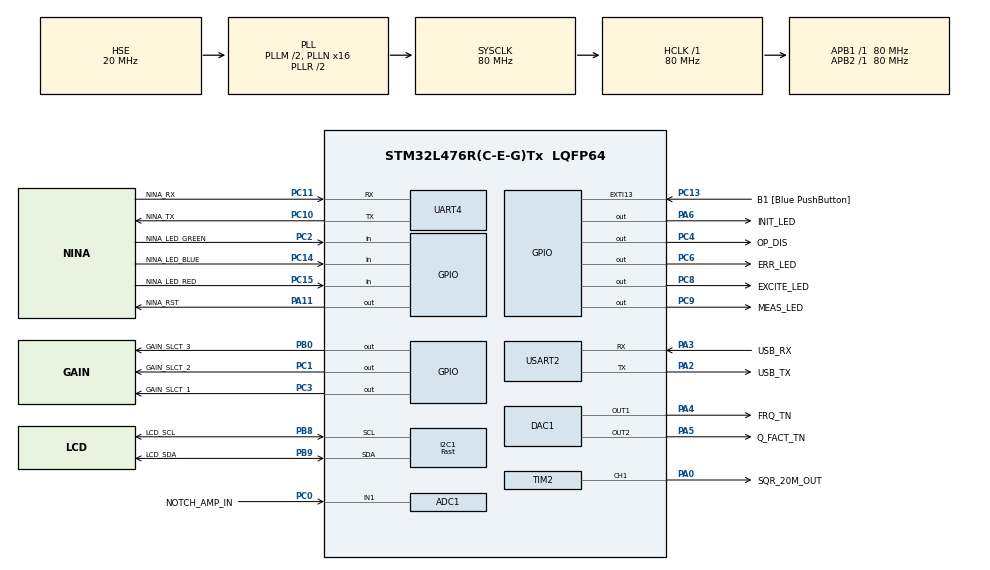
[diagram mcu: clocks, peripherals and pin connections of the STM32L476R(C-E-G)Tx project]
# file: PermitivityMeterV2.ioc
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ADC1.Channel-0\#ChannelRegularConversion=ADC_CHANNEL_1
ADC1.ContinuousConvMode=ENABLE
ADC1.DMAContinuousRequests=ENABLE
ADC1.NbrOfConversionFlag=1
ADC1.OffsetNumber-0\#ChannelRegularConversion=ADC_OFFSET_NONE
ADC1.OversamplingMode=DISABLE
ADC1.Rank-0\#ChannelRegularConversion=1
ADC1.SamplingTime-0\#ChannelRegularConversion=ADC_SAMPLETIME_47CYCLES_5
ADC1.master=1
DAC1.DAC_Channel-DAC_OUT2_ExtAndInt=DAC_CHANNEL_2
Dma.ADC1.0.Direction=DMA_PERIPH_TO_MEMORY
Dma.ADC1.0.Instance=DMA1_Channel1
Dma.ADC1.0.MemDataAlignment=DMA_MDATAALIGN_HALFWORD
Dma.ADC1.0.MemInc=DMA_MINC_ENABLE
Dma.ADC1.0.Mode=DMA_CIRCULAR
Dma.ADC1.0.PeriphDataAlignment=DMA_PDATAALIGN_HALFWORD
Dma.ADC1.0.PeriphInc=DMA_PINC_DISABLE
Dma.ADC1.0.Priority=DMA_PRIORITY_HIGH
Dma.DAC_CH1.2.Direction=DMA_MEMORY_TO_PERIPH
Dma.DAC_CH1.2.Instance=DMA1_Channel3
Dma.DAC_CH1.2.MemDataAlignment=DMA_MDATAALIGN_HALFWORD
Dma.DAC_CH1.2.MemInc=DMA_MINC_ENABLE
Dma.DAC_CH1.2.Mode=DMA_NORMAL
Dma.DAC_CH1.2.PeriphDataAlignment=DMA_PDATAALIGN_HALFWORD
Dma.DAC_CH1.2.PeriphInc=DMA_PINC_DISABLE
Dma.DAC_CH1.2.Priority=DMA_PRIORITY_LOW
Dma.DAC_CH2.1.Direction=DMA_MEMORY_TO_PERIPH
Dma.DAC_CH2.1.Instance=DMA1_Channel4
Dma.DAC_CH2.1.MemDataAlignment=DMA_MDATAALIGN_HALFWORD
Dma.DAC_CH2.1.MemInc=DMA_MINC_ENABLE
Dma.DAC_CH2.1.Mode=DMA_NORMAL
Dma.DAC_CH2.1.PeriphDataAlignment=DMA_PDATAALIGN_HALFWORD
Dma.DAC_CH2.1.PeriphInc=DMA_PINC_DISABLE
Dma.DAC_CH2.1.Priority=DMA_PRIORITY_LOW
Dma.Request0=ADC1
Dma.Request1=DAC_CH2
Dma.Request2=DAC_CH1
Dma.Request3=USART2_RX
Dma.Request4=USART2_TX
Dma.USART2_RX.3.Direction=DMA_PERIPH_TO_MEMORY
Dma.USART2_RX.3.Instance=DMA1_Channel6
Dma.USART2_RX.3.MemDataAlignment=DMA_MDATAALIGN_BYTE
Dma.USART2_RX.3.MemInc=DMA_MINC_ENABLE
Dma.USART2_RX.3.Mode=DMA_NORMAL
Dma.USART2_RX.3.PeriphDataAlignment=DMA_PDATAALIGN_BYTE
Dma.USART2_RX.3.PeriphInc=DMA_PINC_DISABLE
Dma.USART2_RX.3.Priority=DMA_PRIORITY_LOW
Dma.USART2_TX.4.Direction=DMA_MEMORY_TO_PERIPH
Dma.USART2_TX.4.Instance=DMA1_Channel7
Dma.USART2_TX.4.MemDataAlignment=DMA_MDATAALIGN_BYTE
Dma.USART2_TX.4.MemInc=DMA_MINC_ENABLE
Dma.USART2_TX.4.Mode=DMA_NORMAL
Dma.USART2_TX.4.PeriphDataAlignment=DMA_PDATAALIGN_BYTE
Dma.USART2_TX.4.PeriphInc=DMA_PINC_DISABLE
Dma.USART2_TX.4.Priority=DMA_PRIORITY_LOW
I2C1.I2C_Speed_Mode=I2C_Fast
I2C1.Timing=0x00F12981
IWDG.Prescaler=IWDG_PRESCALER_256
Mcu.Family=STM32L4
Mcu.Name=STM32L476R(C-E-G)Tx
Mcu.Package=LQFP64
NVIC.DMA1_Channel1_IRQn=true\:0\:0\:false\:false\:true\:false\:true\:true
NVIC.DMA1_Channel3_IRQn=true\:0\:0\:false\:false\:true\:false\:true\:true
NVIC.DMA1_Channel4_IRQn=true\:0\:0\:false\:false\:true\:false\:true\:true
NVIC.DMA1_Channel6_IRQn=true\:0\:0\:false\:false\:true\:false\:true\:true
NVIC.DMA1_Channel7_IRQn=true\:0\:0\:false\:false\:true\:false\:true\:true
NVIC.PriorityGroup=NVIC_PRIORITYGROUP_4
NVIC.USART2_IRQn=true\:0\:0\:false\:false\:true\:true\:true\:true
PA0.GPIO_Label=SQR_20M_OUT
PA0.GPIO_ModeDefaultPP=GPIO_MODE_AF_PP
PA0.GPIO_PuPd=GPIO_NOPULL
PA0.GPIO_Speed=GPIO_SPEED_FREQ_VERY_HIGH
PA0.Signal=S_TIM2_CH1
PA11.GPIO_Label=NINA_RST 
PA11.Signal=GPIO_Output
PA13\ (JTMS-SWDIO).GPIO_Label=TMS
PA13\ (JTMS-SWDIO).Mode=Trace_Asynchronous_SW
PA13\ (JTMS-SWDIO).Signal=SYS_JTMS-SWDIO
PA14\ (JTCK-SWCLK).GPIO_Label=TCK
PA14\ (JTCK-SWCLK).Mode=Trace_Asynchronous_SW
PA14\ (JTCK-SWCLK).Signal=SYS_JTCK-SWCLK
PA2.GPIO_Label=USB_TX
PA2.Mode=Asynchronous
PA2.Signal=USART2_TX
PA3.GPIO_Label=USB_RX
PA3.Mode=Asynchronous
PA3.Signal=USART2_RX
PA4.GPIO_Label=FRQ_TN
PA4.Signal=COMP_DAC11_group
PA5.GPIO_Label=Q_FACT_TN
PA5.Signal=COMP_DAC12_group
PA6.GPIO_Label=INIT_LED
PA6.Signal=GPIO_Output
PB0.GPIO_Label=GAIN_SLCT_3
PB0.Signal=GPIO_Output
PB3\ (JTDO-TRACESWO).GPIO_Label=SWO
PB3\ (JTDO-TRACESWO).Mode=Trace_Asynchronous_SW
PB3\ (JTDO-TRACESWO).Signal=SYS_JTDO-SWO
PB8.GPIO_FM6=SYSCFG_FASTMODEPLUS_PB6
PB8.GPIO_Label=LCD_SCL
PB8.Mode=I2C
PB8.Signal=I2C1_SCL
PB9.GPIO_FM9=SYSCFG_FASTMODEPLUS_PB9
PB9.GPIO_Label=LCD_SDA
PB9.Mode=I2C
PB9.Signal=I2C1_SDA
PC0.GPIO_Label=NOTCH_AMP_IN
PC0.Signal=ADCx_IN1
PC1.GPIO_Label=GAIN_SLCT_2
PC1.GPIO_Speed=GPIO_SPEED_FREQ_HIGH
PC1.Signal=GPIO_Output
PC10.GPIO_Label=NINA_TX
PC10.Mode=Asynchronous
PC10.Signal=UART4_TX
PC11.GPIO_Label=NINA_RX
PC11.Mode=Asynchronous
PC11.Signal=UART4_RX
PC13.GPIO_Label=B1 [Blue PushButton]
PC13.GPIO_ModeDefaultEXTI=GPIO_MODE_IT_FALLING
PC13.GPIO_PuPd=GPIO_NOPULL
PC13.Signal=GPXTI13
PC14-OSC32_IN\ (PC14).GPIO_Label=NINA_LED_BLUE
PC14-OSC32_IN\ (PC14).Signal=GPIO_Input
PC15-OSC32_OUT\ (PC15).GPIO_Label=NINA_LED_RED
PC15-OSC32_OUT\ (PC15).Signal=GPIO_Input
PC2.GPIO_Label=NINA_LED_GREEN
PC2.Signal=GPIO_Input
PC3.GPIO_Label=GAIN_SLCT_1
PC3.GPIO_Speed=GPIO_SPEED_FREQ_HIGH
PC3.Signal=GPIO_Output
PC4.GPIO_Label=OP_DIS 
PC4.Signal=GPIO_Output
PC6.GPIO_Label=ERR_LED
PC6.Signal=GPIO_Output
PC8.GPIO_Label=EXCITE_LED
PC8.Signal=GPIO_Output
PC9.GPIO_Label=MEAS_LED
PC9.Signal=GPIO_Output
PH0-OSC_IN\ (PH0).Mode=HSE-External-Oscillator
PH0-OSC_IN\ (PH0).Signal=RCC_OSC_IN
PH1-OSC_OUT\ (PH1).Mode=HSE-External-Oscillator
PH1-OSC_OUT\ (PH1).Signal=RCC_OSC_OUT
ProjectManager.HeapSize=0x200
ProjectManager.StackSize=0x400
ProjectManager.TargetToolchain=STM32CubeIDE
RCC.ADCCLockSelection=RCC_ADCCLKSOURCE_SYSCLK
RCC.ADCFreq_Value=80000000
RCC.AHBFreq_Value=80000000
RCC.APB1Freq_Value=80000000
RCC.APB1TimFreq_Value=80000000
RCC.APB2Freq_Value=80000000
RCC.APB2TimFreq_Value=80000000
RCC.CortexFreq_Value=80000000
RCC.EnbaleCSS=true
RCC.HCLKFreq_Value=80000000
RCC.HSE_VALUE=20000000
RCC.HSI_VALUE=16000000
RCC.LSE_VALUE=32768
RCC.MSIClockRange=RCC_MSIRANGE_4
RCC.MSI_VALUE=1000000
RCC.PLLM=2
RCC.PLLN=16
RCC.PLLSAI1N=16
RCC.PLLSourceVirtual=RCC_PLLSOURCE_HSE
RCC.PREFETCH_ENABLE=1
RCC.RCC_MCO1Source=RCC_MCO1SOURCE_HSE
RCC.SYSCLKFreq_VALUE=80000000
RCC.SYSCLKSource=RCC_SYSCLKSOURCE_PLLCLK
RCC.UART4CLockSelection=RCC_UART4CLKSOURCE_SYSCLK
RCC.USBFreq_Value=80000000
RCC.VCOOutputFreq_Value=160000000
SH.ADCx_IN1.0=ADC1_IN1,IN1-Single-Ended
SH.COMP_DAC11_group.0=DAC1_OUT1,DAC_OUT1_ExtAndInt
SH.COMP_DAC12_group.0=DAC1_OUT2,DAC_OUT2_ExtAndInt
SH.S_TIM2_CH1.0=TIM2_CH1,PWM Generation1 CH1
TIM2.Channel-PWM\ Generation1\ CH1=TIM_CHANNEL_1
TIM3.Period=65535
USART2.VirtualMode-Asynchronous=VM_ASYNC
VP_IWDG_VS_IWDG.Mode=IWDG_Activate
VP_TIM1_VS_ClockSourceINT.Mode=Internal
VP_TIM3_VS_ClockSourceINT.Mode=Internal
VP_TIM6_VS_ClockSourceINT.Mode=Enable_Timer
board=NUCLEO-L476RG

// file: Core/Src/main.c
/* USER CODE BEGIN Header */
/**
  ******************************************************************************
  * @file           : main.c
  * @brief          : Main program body
  ******************************************************************************
  * @attention
  *
  * Copyright (c) 2025 STMicroelectronics.
  * All rights reserved.
  *
  * This software is licensed under terms that can be found in the LICENSE file
  * in the root directory of this software component.
  * If no LICENSE file comes with this software, it is provided AS-IS.
  *
  ******************************************************************************
  */
/* USER CODE END Header */
#include "main.h"

/* USER CODE BEGIN Includes */
#include <string.h>
#include <stdio.h>
#include "hl/hal_pwm.h"
#include "fsm_main.h"
#include "hl/hal_dac.h"
#include "test/test_hal_dac.h"
#include "hl/hal_adc.h"
#include "hl/hal_gpio.h"
/* USER CODE END Includes */

/* USER CODE BEGIN PD */

/* Set to 1 to build a minimal firmware that only brings up USART2 (ST-LINK VCP)
 * and provides a simple polling echo/heartbeat. This is for debugging the PC
 * UART link without any other HW init.
 */
#define UART_SMOKE_TEST 0

/* USER CODE END PD */

ADC_HandleTypeDef hadc1;
DMA_HandleTypeDef hdma_adc1;

DAC_HandleTypeDef hdac1;
DMA_HandleTypeDef hdma_dac_ch2;
DMA_HandleTypeDef hdma_dac_ch1;

I2C_HandleTypeDef hi2c1;

IWDG_HandleTypeDef hiwdg;

TIM_HandleTypeDef htim1;
TIM_HandleTypeDef htim2;
TIM_HandleTypeDef htim3;
TIM_HandleTypeDef htim6;

UART_HandleTypeDef huart4;
UART_HandleTypeDef huart2;
DMA_HandleTypeDef hdma_usart2_rx;
DMA_HandleTypeDef hdma_usart2_tx;

/* USER CODE BEGIN PV */

/* Set to 1 when SystemClock_Config() falls back to MSI because HSE/PLL failed. */
volatile uint8_t g_clock_fallback_active = 0U;

/* USER CODE END PV */

void SystemClock_Config(void);
static void MX_GPIO_Init(void);
static void MX_DMA_Init(void);
static void MX_ADC1_Init(void);
static void MX_UART4_Init(void);
static void MX_DAC1_Init(void);
static void MX_IWDG_Init(void);
static void MX_TIM1_Init(void);
static void MX_USART2_UART_Init(void);
static void MX_TIM6_Init(void);
static void MX_TIM3_Init(void);
static void MX_TIM2_Init(void);
static void MX_I2C1_Init(void);

/* USER CODE BEGIN 0 */

/*
static void uart2_panic_print(const char *msg)
{
   Best-effort: bring up USART2 using the current clock domain (even if
    SystemClock_Config() failed and we are still on the reset-default MSI).

  (void)MX_USART2_UART_Init();
  const char *prefix = "STAT:ERR:";
  (void)HAL_UART_Transmit(&huart2, (uint8_t *)prefix, (uint16_t)strlen(prefix), 1000U);
  if (msg != NULL) {
    (void)HAL_UART_Transmit(&huart2, (uint8_t *)msg, (uint16_t)strlen(msg), 1000U);
  }
  const char *suffix = "\n";
  (void)HAL_UART_Transmit(&huart2, (uint8_t *)suffix, (uint16_t)strlen(suffix), 1000U);
}
*/
/* USER CODE END 0 */

int main(void)
{

  /* MCU Configuration--------------------------------------------------------*/

  /* Reset of all peripherals, Initializes the Flash interface and the Systick. */
  HAL_Init();

  /* Configure the system clock */
  SystemClock_Config();

  /* Initialize all configured peripherals */
  MX_GPIO_Init();
  MX_DMA_Init();
  MX_ADC1_Init();
  MX_UART4_Init();
  MX_DAC1_Init();
  MX_IWDG_Init();
  MX_TIM1_Init();
  MX_USART2_UART_Init();
  MX_TIM6_Init();
  MX_TIM3_Init();
  MX_TIM2_Init();
  MX_I2C1_Init();
  /* USER CODE BEGIN 2 */

  /* ========================================================================== */
  /*                         DRIVER INITIALIZATION                              */
  /* ========================================================================== */

  /* Initialize DAC Driver */
  if (HL_DAC_Init(&hdac1) != DAC_OK)
  {
    Error_Handler();
  }
  HL_DAC_Start(DAC_CH_FREQ_TUNE);  /* PA4 - Frequency Tuning */
  HL_DAC_Start(DAC_CH_Q_FACTOR);   /* PA5 - Q-Factor Tuning */

  /* Initialize ADC Driver */
  if (HL_ADC_Init(&hadc1, &htim6) != ADC_OK)
  {
    Error_Handler();
  }
  if (HL_ADC_Start() != ADC_OK)
  {
    Error_Handler();
  }

  /* Initialize PWM Driver (20 MHz excitation signal on PA0) */
  HAL_PWM_Init(&htim2);
  HAL_PWM_SetFrequency(20000000UL);
  HAL_PWM_SetDutyCycle(50);
  HAL_PWM_Start();
  // Test_HL_DAC_GenerateWaveform(&hdac1,&hiwdg);
  /* Note: PWM is NOT started here - FSM controls when to start excitation */

  /* Turn on Init LED to indicate successful initialization */
  HL_GPIO_Write(HL_GPIO_LED_INIT, HL_GPIO_HIGH);

  /* Hardware-visible alarm: external clock failed, running on MSI fallback. */
  if (g_clock_fallback_active) {
    (void)HL_GPIO_Write(HL_GPIO_LED_ERR, HL_GPIO_HIGH);
  }

  /* -------------------------------------------------------------------------- */
  /* TEST 9: Verification of New Pin Changes (COMMENTED OUT FOR PRODUCTION)     */
  /* Verifies:                                                                  */
  /*   - Gain Select 1 (PC3)                                                    */
  /*   - Gain Select 2 (PC1)                                                    */
  /*   - LEDs: INIT(PB8), MEAS(PC9), EXCITE(PC8), ERR(PC6)                      */
  /*   - NINA DTR (PB11)                                                        */
  /* Expected:                                                                  */
  /*   - Gain Selects & DTR toggle every 1s (approx)                            */
  /*   - LEDs chase sequence (250ms each)                                       */
  /* -------------------------------------------------------------------------- */
  /*
  while (1)
  {
    HAL_IWDG_Refresh(&hiwdg);

    // tests for the new pins
    HL_GPIO_Toggle(HL_GPIO_NINA_DTR); // PB11
    HL_GPIO_Toggle(HL_GPIO_NINA_STOP); // PA12
    HL_GPIO_Toggle(HL_GPIO_NINA_RST); // PA11
    // Toggle 1-second interval pins (4 steps x 250ms = 1s)
    HL_GPIO_Toggle(HL_GPIO_RF_GAIN_0);      // PC3
    HL_GPIO_Toggle(HL_GPIO_RF_GAIN_1);      // PC1
    HAL_GPIO_TogglePin(NINA_DTR_GPIO_Port, NINA_DTR_Pin); // PB11

    // LED Chase Sequence
    HL_GPIO_Write(HL_GPIO_LED_INIT, HL_GPIO_HIGH);   // PB8 ON
    HL_GPIO_Write(HL_GPIO_LED_MEAS, HL_GPIO_LOW);
    HL_GPIO_Write(HL_GPIO_LED_EXCITE, HL_GPIO_LOW);
    HL_GPIO_Write(HL_GPIO_LED_ERR, HL_GPIO_LOW);
    HAL_Delay(250);

    HL_GPIO_Write(HL_GPIO_LED_INIT, HL_GPIO_LOW);
    HL_GPIO_Write(HL_GPIO_LED_MEAS, HL_GPIO_HIGH);   // PC9 ON
    HAL_Delay(250);

    HL_GPIO_Write(HL_GPIO_LED_MEAS, HL_GPIO_LOW);
    HL_GPIO_Write(HL_GPIO_LED_EXCITE, HL_GPIO_HIGH); // PC8 ON
    HAL_Delay(250);

    HL_GPIO_Write(HL_GPIO_LED_EXCITE, HL_GPIO_LOW);
    HL_GPIO_Write(HL_GPIO_LED_ERR, HL_GPIO_HIGH);    // PC6 ON
    HAL_Delay(250);
  }
  */

  /* ========================================================================== */
  /*                         FSM INITIALIZATION                                 */
  /* ========================================================================== */

  FSM_Init();
  /* USER CODE END 2 */

  /* Infinite loop */
  /* USER CODE BEGIN WHILE */

  while (1)
  {
    HAL_IWDG_Refresh(&hiwdg);
    FSM_RunOnce();

    /* USER CODE END WHILE */

  }
}

void SystemClock_Config(void)
{
  RCC_OscInitTypeDef RCC_OscInitStruct = {0};
  RCC_ClkInitTypeDef RCC_ClkInitStruct = {0};

  /** Configure the main internal regulator output voltage
  */
  if (HAL_PWREx_ControlVoltageScaling(PWR_REGULATOR_VOLTAGE_SCALE1) != HAL_OK)
  {
    Error_Handler();
  }

  /** Initializes the RCC Oscillators according to the specified parameters
  * in the RCC_OscInitTypeDef structure.
  */
  RCC_OscInitStruct.OscillatorType = RCC_OSCILLATORTYPE_LSI|RCC_OSCILLATORTYPE_HSE;
  RCC_OscInitStruct.HSEState = RCC_HSE_ON;
  RCC_OscInitStruct.LSIState = RCC_LSI_ON;
  RCC_OscInitStruct.PLL.PLLState = RCC_PLL_ON;
  RCC_OscInitStruct.PLL.PLLSource = RCC_PLLSOURCE_HSE;
  RCC_OscInitStruct.PLL.PLLM = 2;
  RCC_OscInitStruct.PLL.PLLN = 16;
  RCC_OscInitStruct.PLL.PLLP = RCC_PLLP_DIV7;
  RCC_OscInitStruct.PLL.PLLQ = RCC_PLLQ_DIV2;
  RCC_OscInitStruct.PLL.PLLR = RCC_PLLR_DIV2;
  if (HAL_RCC_OscConfig(&RCC_OscInitStruct) != HAL_OK)
  {
    Error_Handler();
  }

  /** Initializes the CPU, AHB and APB buses clocks
  */
  RCC_ClkInitStruct.ClockType = RCC_CLOCKTYPE_HCLK|RCC_CLOCKTYPE_SYSCLK
                              |RCC_CLOCKTYPE_PCLK1|RCC_CLOCKTYPE_PCLK2;
  RCC_ClkInitStruct.SYSCLKSource = RCC_SYSCLKSOURCE_PLLCLK;
  RCC_ClkInitStruct.AHBCLKDivider = RCC_SYSCLK_DIV1;
  RCC_ClkInitStruct.APB1CLKDivider = RCC_HCLK_DIV1;
  RCC_ClkInitStruct.APB2CLKDivider = RCC_HCLK_DIV1;

  if (HAL_RCC_ClockConfig(&RCC_ClkInitStruct, FLASH_LATENCY_4) != HAL_OK)
  {
    Error_Handler();
  }
  HAL_RCC_MCOConfig(RCC_MCO1, RCC_MCO1SOURCE_HSE, RCC_MCODIV_1);

  /** Enables the Clock Security System
  */
  HAL_RCC_EnableCSS();
}

static void MX_ADC1_Init(void)
{

  ADC_MultiModeTypeDef multimode = {0};
  ADC_ChannelConfTypeDef sConfig = {0};

  /** Common config
  */
  hadc1.Instance = ADC1;
  hadc1.Init.ClockPrescaler = ADC_CLOCK_ASYNC_DIV1;
  hadc1.Init.Resolution = ADC_RESOLUTION_12B;
  hadc1.Init.DataAlign = ADC_DATAALIGN_RIGHT;
  hadc1.Init.ScanConvMode = ADC_SCAN_DISABLE;
  hadc1.Init.EOCSelection = ADC_EOC_SINGLE_CONV;
  hadc1.Init.LowPowerAutoWait = DISABLE;
  hadc1.Init.ContinuousConvMode = ENABLE;
  hadc1.Init.NbrOfConversion = 1;
  hadc1.Init.DiscontinuousConvMode = DISABLE;
  hadc1.Init.ExternalTrigConv = ADC_SOFTWARE_START;
  hadc1.Init.ExternalTrigConvEdge = ADC_EXTERNALTRIGCONVEDGE_NONE;
  hadc1.Init.DMAContinuousRequests = ENABLE;
  hadc1.Init.Overrun = ADC_OVR_DATA_PRESERVED;
  hadc1.Init.OversamplingMode = DISABLE;
  if (HAL_ADC_Init(&hadc1) != HAL_OK)
  {
    Error_Handler();
  }

  /** Configure the ADC multi-mode
  */
  multimode.Mode = ADC_MODE_INDEPENDENT;
  if (HAL_ADCEx_MultiModeConfigChannel(&hadc1, &multimode) != HAL_OK)
  {
    Error_Handler();
  }

  /** Configure Regular Channel
  */
  sConfig.Channel = ADC_CHANNEL_1;
  sConfig.Rank = ADC_REGULAR_RANK_1;
  sConfig.SamplingTime = ADC_SAMPLETIME_47CYCLES_5;
  sConfig.SingleDiff = ADC_SINGLE_ENDED;
  sConfig.OffsetNumber = ADC_OFFSET_NONE;
  sConfig.Offset = 0;
  if (HAL_ADC_ConfigChannel(&hadc1, &sConfig) != HAL_OK)
  {
    Error_Handler();
  }

}

static void MX_DAC1_Init(void)
{

  DAC_ChannelConfTypeDef sConfig = {0};

  /** DAC Initialization
  */
  hdac1.Instance = DAC1;
  if (HAL_DAC_Init(&hdac1) != HAL_OK)
  {
    Error_Handler();
  }

  /** DAC channel OUT1 config
  */
  sConfig.DAC_SampleAndHold = DAC_SAMPLEANDHOLD_DISABLE;
  sConfig.DAC_Trigger = DAC_TRIGGER_NONE;
  sConfig.DAC_OutputBuffer = DAC_OUTPUTBUFFER_ENABLE;
  sConfig.DAC_ConnectOnChipPeripheral = DAC_CHIPCONNECT_ENABLE;
  sConfig.DAC_UserTrimming = DAC_TRIMMING_FACTORY;
  if (HAL_DAC_ConfigChannel(&hdac1, &sConfig, DAC_CHANNEL_1) != HAL_OK)
  {
    Error_Handler();
  }

  /** DAC channel OUT2 config
  */
  if (HAL_DAC_ConfigChannel(&hdac1, &sConfig, DAC_CHANNEL_2) != HAL_OK)
  {
    Error_Handler();
  }

}

static void MX_I2C1_Init(void)
{

  hi2c1.Instance = I2C1;
  hi2c1.Init.Timing = 0x00F12981;
  hi2c1.Init.OwnAddress1 = 0;
  hi2c1.Init.AddressingMode = I2C_ADDRESSINGMODE_7BIT;
  hi2c1.Init.DualAddressMode = I2C_DUALADDRESS_DISABLE;
  hi2c1.Init.OwnAddress2 = 0;
  hi2c1.Init.OwnAddress2Masks = I2C_OA2_NOMASK;
  hi2c1.Init.GeneralCallMode = I2C_GENERALCALL_DISABLE;
  hi2c1.Init.NoStretchMode = I2C_NOSTRETCH_DISABLE;
  if (HAL_I2C_Init(&hi2c1) != HAL_OK)
  {
    Error_Handler();
  }

  /** Configure Analogue filter
  */
  if (HAL_I2CEx_ConfigAnalogFilter(&hi2c1, I2C_ANALOGFILTER_ENABLE) != HAL_OK)
  {
    Error_Handler();
  }

  /** Configure Digital filter
  */
  if (HAL_I2CEx_ConfigDigitalFilter(&hi2c1, 0) != HAL_OK)
  {
    Error_Handler();
  }

}

static void MX_IWDG_Init(void)
{

  hiwdg.Instance = IWDG;
  hiwdg.Init.Prescaler = IWDG_PRESCALER_256;
  hiwdg.Init.Window = 4095;
  hiwdg.Init.Reload = 4095;
  if (HAL_IWDG_Init(&hiwdg) != HAL_OK)
  {
    Error_Handler();
  }

}

static void MX_TIM1_Init(void)
{

  TIM_ClockConfigTypeDef sClockSourceConfig = {0};
  TIM_MasterConfigTypeDef sMasterConfig = {0};

  htim1.Instance = TIM1;
  htim1.Init.Prescaler = 0;
  htim1.Init.CounterMode = TIM_COUNTERMODE_UP;
  htim1.Init.Period = 65535;
  htim1.Init.ClockDivision = TIM_CLOCKDIVISION_DIV1;
  htim1.Init.RepetitionCounter = 0;
  htim1.Init.AutoReloadPreload = TIM_AUTORELOAD_PRELOAD_DISABLE;
  if (HAL_TIM_Base_Init(&htim1) != HAL_OK)
  {
    Error_Handler();
  }
  sClockSourceConfig.ClockSource = TIM_CLOCKSOURCE_INTERNAL;
  if (HAL_TIM_ConfigClockSource(&htim1, &sClockSourceConfig) != HAL_OK)
  {
    Error_Handler();
  }
  sMasterConfig.MasterOutputTrigger = TIM_TRGO_RESET;
  sMasterConfig.MasterOutputTrigger2 = TIM_TRGO2_RESET;
  sMasterConfig.MasterSlaveMode = TIM_MASTERSLAVEMODE_DISABLE;
  if (HAL_TIMEx_MasterConfigSynchronization(&htim1, &sMasterConfig) != HAL_OK)
  {
    Error_Handler();
  }
  /* USER CODE BEGIN TIM1_Init 2 */
  	// pwm_is_running = 0;
     //pwm_duty_cycle = PWM_DUTY_CYCLE_DEFAULT;
  /* USER CODE END TIM1_Init 2 */

}

static void MX_TIM2_Init(void)
{

  TIM_MasterConfigTypeDef sMasterConfig = {0};
  TIM_OC_InitTypeDef sConfigOC = {0};

  htim2.Instance = TIM2;
  htim2.Init.Prescaler = 0;
  htim2.Init.CounterMode = TIM_COUNTERMODE_UP;
  htim2.Init.Period = 4294967295;
  htim2.Init.ClockDivision = TIM_CLOCKDIVISION_DIV1;
  htim2.Init.AutoReloadPreload = TIM_AUTORELOAD_PRELOAD_DISABLE;
  if (HAL_TIM_PWM_Init(&htim2) != HAL_OK)
  {
    Error_Handler();
  }
  sMasterConfig.MasterOutputTrigger = TIM_TRGO_RESET;
  sMasterConfig.MasterSlaveMode = TIM_MASTERSLAVEMODE_DISABLE;
  if (HAL_TIMEx_MasterConfigSynchronization(&htim2, &sMasterConfig) != HAL_OK)
  {
    Error_Handler();
  }
  sConfigOC.OCMode = TIM_OCMODE_PWM1;
  sConfigOC.Pulse = 0;
  sConfigOC.OCPolarity = TIM_OCPOLARITY_HIGH;
  sConfigOC.OCFastMode = TIM_OCFAST_DISABLE;
  if (HAL_TIM_PWM_ConfigChannel(&htim2, &sConfigOC, TIM_CHANNEL_1) != HAL_OK)
  {
    Error_Handler();
  }
  HAL_TIM_MspPostInit(&htim2);

}

static void MX_TIM3_Init(void)
{

  TIM_ClockConfigTypeDef sClockSourceConfig = {0};
  TIM_MasterConfigTypeDef sMasterConfig = {0};

  htim3.Instance = TIM3;
  htim3.Init.Prescaler = 0;
  htim3.Init.CounterMode = TIM_COUNTERMODE_UP;
  htim3.Init.Period = 65535;
  htim3.Init.ClockDivision = TIM_CLOCKDIVISION_DIV1;
  htim3.Init.AutoReloadPreload = TIM_AUTORELOAD_PRELOAD_DISABLE;
  if (HAL_TIM_Base_Init(&htim3) != HAL_OK)
  {
    Error_Handler();
  }
  sClockSourceConfig.ClockSource = TIM_CLOCKSOURCE_INTERNAL;
  if (HAL_TIM_ConfigClockSource(&htim3, &sClockSourceConfig) != HAL_OK)
  {
    Error_Handler();
  }
  sMasterConfig.MasterOutputTrigger = TIM_TRGO_RESET;
  sMasterConfig.MasterSlaveMode = TIM_MASTERSLAVEMODE_DISABLE;
  if (HAL_TIMEx_MasterConfigSynchronization(&htim3, &sMasterConfig) != HAL_OK)
  {
    Error_Handler();
  }

}

static void MX_TIM6_Init(void)
{

  TIM_MasterConfigTypeDef sMasterConfig = {0};

  htim6.Instance = TIM6;
  htim6.Init.Prescaler = 0;
  htim6.Init.CounterMode = TIM_COUNTERMODE_UP;
  htim6.Init.Period = 65535;
  htim6.Init.AutoReloadPreload = TIM_AUTORELOAD_PRELOAD_DISABLE;
  if (HAL_TIM_Base_Init(&htim6) != HAL_OK)
  {
    Error_Handler();
  }
  sMasterConfig.MasterOutputTrigger = TIM_TRGO_RESET;
  sMasterConfig.MasterSlaveMode = TIM_MASTERSLAVEMODE_DISABLE;
  if (HAL_TIMEx_MasterConfigSynchronization(&htim6, &sMasterConfig) != HAL_OK)
  {
    Error_Handler();
  }

}

static void MX_UART4_Init(void)
{

  huart4.Instance = UART4;
  huart4.Init.BaudRate = 115200;
  huart4.Init.WordLength = UART_WORDLENGTH_8B;
  huart4.Init.StopBits = UART_STOPBITS_1;
  huart4.Init.Parity = UART_PARITY_NONE;
  huart4.Init.Mode = UART_MODE_TX_RX;
  huart4.Init.HwFlowCtl = UART_HWCONTROL_RTS_CTS;
  huart4.Init.OverSampling = UART_OVERSAMPLING_16;
  huart4.Init.OneBitSampling = UART_ONE_BIT_SAMPLE_DISABLE;
  huart4.AdvancedInit.AdvFeatureInit = UART_ADVFEATURE_NO_INIT;
  if (HAL_UART_Init(&huart4) != HAL_OK)
  {
    Error_Handler();
  }

}

static void MX_USART2_UART_Init(void)
{

  huart2.Instance = USART2;
  huart2.Init.BaudRate = 115200;
  huart2.Init.WordLength = UART_WORDLENGTH_8B;
  huart2.Init.StopBits = UART_STOPBITS_1;
  huart2.Init.Parity = UART_PARITY_NONE;
  huart2.Init.Mode = UART_MODE_TX_RX;
  huart2.Init.HwFlowCtl = UART_HWCONTROL_NONE;
  huart2.Init.OverSampling = UART_OVERSAMPLING_16;
  huart2.Init.OneBitSampling = UART_ONE_BIT_SAMPLE_DISABLE;
  huart2.AdvancedInit.AdvFeatureInit = UART_ADVFEATURE_NO_INIT;
  if (HAL_UART_Init(&huart2) != HAL_OK)
  {
    Error_Handler();
  }

}

static void MX_DMA_Init(void)
{

  /* DMA controller clock enable */
  __HAL_RCC_DMA1_CLK_ENABLE();

  /* DMA interrupt init */
  /* DMA1_Channel1_IRQn interrupt configuration */
  HAL_NVIC_SetPriority(DMA1_Channel1_IRQn, 0, 0);
  HAL_NVIC_EnableIRQ(DMA1_Channel1_IRQn);
  /* DMA1_Channel3_IRQn interrupt configuration */
  HAL_NVIC_SetPriority(DMA1_Channel3_IRQn, 0, 0);
  HAL_NVIC_EnableIRQ(DMA1_Channel3_IRQn);
  /* DMA1_Channel4_IRQn interrupt configuration */
  HAL_NVIC_SetPriority(DMA1_Channel4_IRQn, 0, 0);
  HAL_NVIC_EnableIRQ(DMA1_Channel4_IRQn);
  /* DMA1_Channel6_IRQn interrupt configuration */
  HAL_NVIC_SetPriority(DMA1_Channel6_IRQn, 0, 0);
  HAL_NVIC_EnableIRQ(DMA1_Channel6_IRQn);
  /* DMA1_Channel7_IRQn interrupt configuration */
  HAL_NVIC_SetPriority(DMA1_Channel7_IRQn, 0, 0);
  HAL_NVIC_EnableIRQ(DMA1_Channel7_IRQn);

}

static void MX_GPIO_Init(void)
{
  GPIO_InitTypeDef GPIO_InitStruct = {0};

  /* GPIO Ports Clock Enable */
  __HAL_RCC_GPIOC_CLK_ENABLE();
  __HAL_RCC_GPIOH_CLK_ENABLE();
  __HAL_RCC_GPIOA_CLK_ENABLE();
  __HAL_RCC_GPIOB_CLK_ENABLE();

  /*Configure GPIO pin Output Level */
  HAL_GPIO_WritePin(GPIOC, GAIN_SLCT_2_Pin|GAIN_SLCT_1_Pin|OP_DIS_Pin|ERR_LED_Pin
                          |EXCITE_LED_Pin|MEAS_LED_Pin, GPIO_PIN_RESET);

  /*Configure GPIO pin Output Level */
  HAL_GPIO_WritePin(GPIOB, NINA_DTR_Pin|INIT_LED_Pin, GPIO_PIN_RESET);

  /*Configure GPIO pin Output Level */
  HAL_GPIO_WritePin(GPIOA, NINA_RST_Pin|NINA_STOP_Pin, GPIO_PIN_RESET);

  /*Configure GPIO pin : B1_Pin */
  GPIO_InitStruct.Pin = B1_Pin;
  GPIO_InitStruct.Mode = GPIO_MODE_IT_FALLING;
  GPIO_InitStruct.Pull = GPIO_NOPULL;
  HAL_GPIO_Init(B1_GPIO_Port, &GPIO_InitStruct);

  /*Configure GPIO pins : NINA_LED_BLUE_Pin NINA_LED_RED_Pin NINA_LED_GREEN_Pin */
  GPIO_InitStruct.Pin = NINA_LED_BLUE_Pin|NINA_LED_RED_Pin|NINA_LED_GREEN_Pin;
  GPIO_InitStruct.Mode = GPIO_MODE_INPUT;
  GPIO_InitStruct.Pull = GPIO_NOPULL;
  HAL_GPIO_Init(GPIOC, &GPIO_InitStruct);

  /*Configure GPIO pins : GAIN_SLCT_2_Pin GAIN_SLCT_1_Pin */
  GPIO_InitStruct.Pin = GAIN_SLCT_2_Pin|GAIN_SLCT_1_Pin;
  GPIO_InitStruct.Mode = GPIO_MODE_OUTPUT_PP;
  GPIO_InitStruct.Pull = GPIO_NOPULL;
  GPIO_InitStruct.Speed = GPIO_SPEED_FREQ_HIGH;
  HAL_GPIO_Init(GPIOC, &GPIO_InitStruct);

  /*Configure GPIO pins : OP_DIS_Pin ERR_LED_Pin EXCITE_LED_Pin MEAS_LED_Pin */
  GPIO_InitStruct.Pin = OP_DIS_Pin|ERR_LED_Pin|EXCITE_LED_Pin|MEAS_LED_Pin;
  GPIO_InitStruct.Mode = GPIO_MODE_OUTPUT_PP;
  GPIO_InitStruct.Pull = GPIO_NOPULL;
  GPIO_InitStruct.Speed = GPIO_SPEED_FREQ_LOW;
  HAL_GPIO_Init(GPIOC, &GPIO_InitStruct);

  /*Configure GPIO pins : NINA_DTR_Pin INIT_LED_Pin */
  GPIO_InitStruct.Pin = NINA_DTR_Pin|INIT_LED_Pin;
  GPIO_InitStruct.Mode = GPIO_MODE_OUTPUT_PP;
  GPIO_InitStruct.Pull = GPIO_NOPULL;
  GPIO_InitStruct.Speed = GPIO_SPEED_FREQ_LOW;
  HAL_GPIO_Init(GPIOB, &GPIO_InitStruct);

  /*Configure GPIO pin : NINA_DSR_Pin */
  GPIO_InitStruct.Pin = NINA_DSR_Pin;
  GPIO_InitStruct.Mode = GPIO_MODE_INPUT;
  GPIO_InitStruct.Pull = GPIO_NOPULL;
  HAL_GPIO_Init(NINA_DSR_GPIO_Port, &GPIO_InitStruct);

  /*Configure GPIO pin : PA8 */
  GPIO_InitStruct.Pin = GPIO_PIN_8;
  GPIO_InitStruct.Mode = GPIO_MODE_AF_PP;
  GPIO_InitStruct.Pull = GPIO_NOPULL;
  GPIO_InitStruct.Speed = GPIO_SPEED_FREQ_LOW;
  GPIO_InitStruct.Alternate = GPIO_AF0_MCO;
  HAL_GPIO_Init(GPIOA, &GPIO_InitStruct);

  /*Configure GPIO pins : NINA_RST_Pin NINA_STOP_Pin */
  GPIO_InitStruct.Pin = NINA_RST_Pin|NINA_STOP_Pin;
  GPIO_InitStruct.Mode = GPIO_MODE_OUTPUT_PP;
  GPIO_InitStruct.Pull = GPIO_NOPULL;
  GPIO_InitStruct.Speed = GPIO_SPEED_FREQ_LOW;
  HAL_GPIO_Init(GPIOA, &GPIO_InitStruct);

}

void Error_Handler(void)
{
  /* USER CODE BEGIN Error_Handler_Debug */
  /* User can add his own implementation to report the HAL error return state */
  // Turn on Error LED (PB1)
  HL_GPIO_Write(HL_GPIO_LED_ERR, HL_GPIO_HIGH);
  __disable_irq();
  while (1)
  {
  }
  /* USER CODE END Error_Handler_Debug */
}
